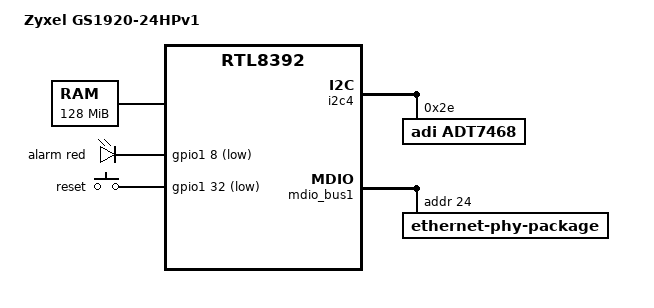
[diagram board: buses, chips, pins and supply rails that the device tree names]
/dts-v1/;

#include "rtl839x_zyxel_gs1920-24hp-common.dtsi"

/ {
	compatible = "zyxel,gs1920-24hp-v1", "realtek,rtl8392-soc";
	model = "Zyxel GS1920-24HPv1";

	memory@0 {
		device_type = "memory";
		reg = <0x0 0x8000000>;
	};

	chosen {
		stdout-path = "serial0:9600n8";
	};

	leds {
		alarm {
			gpios = <&gpio1 8 GPIO_ACTIVE_LOW>;
			function = LED_FUNCTION_FAULT;
			color = <LED_COLOR_ID_RED>;
		};
	};

	keys {
		compatible = "gpio-keys-polled";
		poll-interval = <20>;

		mode {
			label = "reset";
			gpios = <&gpio1 32 GPIO_ACTIVE_LOW>;
			linux,code = <KEY_RESTART>;
		};
	};
};

&i2c4 {
	adt7468: adt7468@2e {
		compatible = "adi,adt7468";
		reg = <0x2e>;
	};
};

&flash_partitions {
	partition@20000 {
		label = "reserved";
		reg = <0x20000 0x90000>;
		read-only;
	};

	partition@b0000 {
		reg = <0xb0000 0xf50000>;
		label = "factory";

		compatible = "fixed-partitions";
		#address-cells = <1>;
		#size-cells = <1>;

		partition@0 {
			label = "loader";
			reg = <0x0 0x10000>;
		};

		partition@10000 {
			label = "firmware";
			reg = <0x10000 0xf40000>;
			compatible = "openwrt,uimage", "denx,uimage";
		};
	};
};

&mdio_bus1 {
	ethernet-phy-package@24 {
		#address-cells = <1>;
		#size-cells = <0>;
		reg = <24>;

		PHY_C22_SFP(48, 24, 0)
		PHY_C22_SFP(49, 25, 1)
		PHY_C22_SFP(50, 26, 2)
		PHY_C22_SFP(51, 27, 3)
	};
};

&pse {
	compatible = "zyxel,gs1920-24hp-v1-pse", "realtek,pse-mcu-gen1-smbus";
};

&switch0 {
	ethernet-ports {
		SWITCH_PORT_SDS(48, 25, 12, 0, qsgmii)
		SWITCH_PORT_SDS(49, 26, 12, 1, qsgmii)
		SWITCH_PORT_SDS(50, 27, 12, 2, qsgmii)
		SWITCH_PORT_SDS(51, 28, 12, 3, qsgmii)
	};
};
